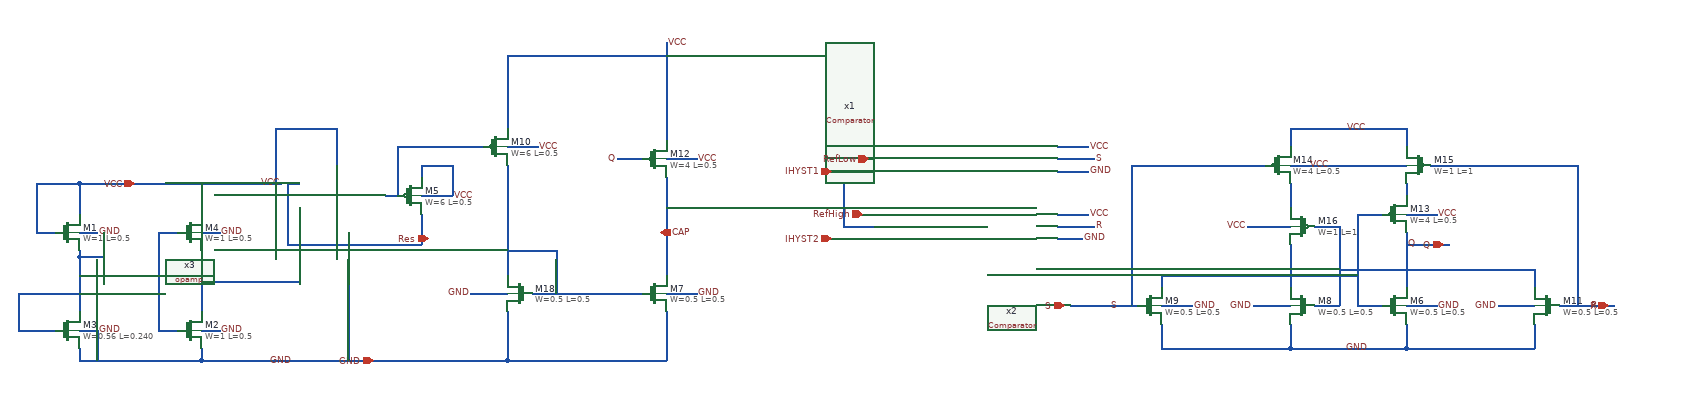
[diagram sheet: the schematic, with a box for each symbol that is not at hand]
v {xschem version=3.1.0 file_version=1.2 }
G {}
K {}
V {}
S {}
E {}
N 170 -340 200 -340 {lab=GND}
N 210 -500 210 -460 {lab=#net1}
N 170 -460 170 -370 {lab=#net1}
N 370 -310 370 -290 {lab=GND}
N 270 -290 370 -290 {lab=GND}
N 170 -310 170 -290 {lab=GND}
N 170 -290 270 -290 {lab=GND}
N 170 -470 170 -460 { lab=#net1}
N 1130 -370 1130 -290 { lab=GND}
N 870 -370 870 -290 { lab=GND}
N 810 -400 870 -400 { lab=GND}
N 1130 -400 1180 -400 { lab=GND}
N 370 -470 370 -370 { lab=#net2}
N 1130 -490 1130 -430 { lab=#net3}
N 910 -400 1090 -400 { lab=#net4}
N 870 -470 950 -470 { lab=#net4}
N 950 -470 950 -400 { lab=#net4}
N 170 -460 210 -460 { lab=#net1}
N 370 -580 370 -530 { lab=VCC}
N 170 -580 170 -530 { lab=VCC}
N 870 -480 870 -430 { lab=#net4}
N 170 -580 500 -580 { lab=VCC}
N 70 -340 130 -340 {
lab=#net1}
N 170 -500 200 -500 {lab=GND}
N 100 -500 130 -500 {
lab=VCC}
N 100 -580 100 -500 {
lab=VCC}
N 100 -580 170 -580 {
lab=VCC}
N 70 -400 70 -340 {
lab=#net1}
N 70 -400 170 -400 {
lab=#net1}
N 370 -340 400 -340 {lab=GND}
N 370 -500 400 -500 {lab=GND}
N 300 -500 330 -500 {
lab=#net1}
N 300 -500 300 -340 {
lab=#net1}
N 300 -340 330 -340 {
lab=#net1}
N 170 -430 300 -430 {
lab=#net1}
N 200 -340 200 -290 {
lab=GND}
N 370 -290 870 -290 {
lab=GND}
N 870 -290 1130 -290 {
lab=GND}
N 1050 -620 1090 -620 { lab=Q}
N 1130 -810 1130 -650 { lab=VCC}
N 870 -790 870 -670 { lab=VCC}
N 870 -640 920 -640 { lab=VCC}
N 1130 -620 1180 -620 { lab=VCC}
N 1130 -590 1130 -570 {
lab=#net3}
N 1130 -570 1130 -490 {
lab=#net3}
N 730 -560 780 -560 { lab=VCC}
N 870 -610 870 -480 {
lab=#net4}
N 870 -790 1130 -790 {
lab=VCC}
N 1420 -640 1470 -640 {
lab=#net3}
N 1420 -640 1420 -510 {
lab=#net3}
N 1420 -510 1470 -510 {
lab=#net3}
N 1450 -620 1470 -620 {
lab=RefLow}
N 1440 -530 1470 -530 {
lab=RefHigh}
N 1770 -640 1820 -640 { lab=VCC}
N 1770 -530 1820 -530 { lab=VCC}
N 1770 -490 1810 -490 {
lab=GND}
N 1770 -600 1820 -600 {
lab=GND}
N 730 -530 730 -490 {
lab=#net5}
N 2090 -380 2150 -380 { lab=GND}
N 2340 -380 2390 -380 { lab=GND}
N 2340 -470 2340 -410 { lab=Q}
N 2150 -460 2150 -410 { lab=#net6}
N 1940 -380 1990 -380 { lab=GND}
N 2490 -380 2550 -380 { lab=GND}
N 2150 -580 2150 -540 {
lab=#net7}
N 2340 -580 2340 -560 {
lab=#net8}
N 2340 -500 2340 -470 {
lab=Q}
N 2550 -440 2550 -410 {
lab=Q}
N 2340 -440 2550 -440 {
lab=Q}
N 1940 -430 1940 -410 {
lab=#net6}
N 1940 -430 2150 -430 {
lab=#net6}
N 1940 -350 1940 -310 {
lab=GND}
N 1940 -310 2150 -310 {
lab=GND}
N 2150 -350 2150 -310 {
lab=GND}
N 2150 -480 2150 -460 {
lab=#net6}
N 2150 -670 2150 -640 {
lab=VCC}
N 2340 -670 2340 -640 {
lab=VCC}
N 1870 -380 1900 -380 {
lab=S}
N 1890 -610 1890 -380 {
lab=S}
N 1890 -610 2110 -610 {
lab=S}
N 2590 -380 2640 -380 {
lab=R}
N 2620 -610 2620 -380 {
lab=R}
N 2380 -610 2620 -610 {
lab=R}
N 2190 -510 2230 -510 {
lab=Q}
N 2230 -510 2230 -380 {
lab=Q}
N 2190 -380 2230 -380 {
lab=Q}
N 2260 -530 2300 -530 {
lab=#net6}
N 2260 -530 2260 -380 {
lab=#net6}
N 2260 -380 2300 -380 {
lab=#net6}
N 2150 -670 2340 -670 {
lab=VCC}
N 2230 -440 2340 -440 {
lab=Q}
N 2150 -430 2260 -430 {
lab=#net6}
N 1770 -620 1830 -620 {
lab=S}
N 1770 -510 1830 -510 {
lab=R}
N 2150 -310 2340 -310 {
lab=GND}
N 2340 -350 2340 -310 {
lab=GND}
N 2550 -350 2550 -310 {
lab=GND}
N 2340 -310 2550 -310 {
lab=GND}
N 2150 -610 2180 -610 {
lab=VCC}
N 2180 -610 2340 -610 {
lab=VCC}
N 2340 -530 2390 -530 {
lab=VCC}
N 2080 -510 2150 -510 {
lab=VCC}
N 590 -670 590 -610 {
lab=VCC}
N 490 -670 590 -670 {
lab=VCC}
N 490 -670 490 -580 {
lab=VCC}
N 610 -500 610 -290 {
lab=GND}
N 670 -560 690 -560 {
lab=#net9}
N 690 -640 830 -640 {
lab=#net9}
N 690 -640 690 -560 {
lab=#net9}
N 530 -540 530 -420 {
lab=#net2}
N 370 -420 530 -420 {
lab=#net2}
N 510 -580 530 -580 {
lab=#net5}
N 510 -580 510 -480 {
lab=#net5}
N 510 -480 730 -480 {
lab=#net5}
N 730 -490 730 -480 {
lab=#net5}
N 730 -610 730 -590 {
lab=VCC}
N 730 -610 780 -610 {
lab=VCC}
N 780 -610 780 -560 {
lab=VCC}
N 1130 -540 1420 -540 {
lab=#net3}
N 1390 -490 1470 -490 {
lab=IHYST2}
N 1390 -600 1470 -600 {
lab=IHYST1}
N 2340 -480 2410 -480 {
lab=GND}
N 2640 -380 2680 -380 {
lab=R}
N 1790 -380 1870 -380 {
lab=S}
C {devices/lab_pin.sym} 200 -340 0 1 {name=p187 lab=GND}
C {devices/lab_pin.sym} 500 -580 1 0 {name=p192 lab=VCC}
C {devices/lab_pin.sym} 810 -400 0 0 {name=p3 lab=GND}
C {devices/lab_pin.sym} 1180 -400 0 1 {name=p5 lab=GND}
C {devices/lab_pin.sym} 520 -290 3 0 {name=p9 lab=GND}
C {sky130_fd_pr/nfet_g5v0d10v5.sym} 1110 -400 0 0 {name=M7
L=0.5
W=0.5
nf=1
mult=1
ad="'int((nf+1)/2) * W/nf * 0.29'" 
pd="'2*int((nf+1)/2) * (W/nf + 0.29)'"
as="'int((nf+2)/2) * W/nf * 0.29'" 
ps="'2*int((nf+2)/2) * (W/nf + 0.29)'"
nrd="'0.29 / W'" nrs="'0.29 / W'"
sa=0 sb=0 sd=0
model=nfet_g5v0d10v5
spiceprefix=X
}
C {sky130_fd_pr/nfet_g5v0d10v5.sym} 890 -400 0 1 {name=M18
L=0.5
W=0.5
nf=1
mult=1
ad="'int((nf+1)/2) * W/nf * 0.29'" 
pd="'2*int((nf+1)/2) * (W/nf + 0.29)'"
as="'int((nf+2)/2) * W/nf * 0.29'" 
ps="'2*int((nf+2)/2) * (W/nf + 0.29)'"
nrd="'0.29 / W'" nrs="'0.29 / W'"
sa=0 sb=0 sd=0
model=nfet_g5v0d10v5
spiceprefix=X
}
C {sky130_fd_pr/nfet_g5v0d10v5.sym} 150 -340 0 0 {name=M3
L=0.240
W=0.56
nf=1
mult=1
ad="'int((nf+1)/2) * W/nf * 0.29'" 
pd="'2*int((nf+1)/2) * (W/nf + 0.29)'"
as="'int((nf+2)/2) * W/nf * 0.29'" 
ps="'2*int((nf+2)/2) * (W/nf + 0.29)'"
nrd="'0.29 / W'" nrs="'0.29 / W'"
sa=0 sb=0 sd=0
model=nfet_g5v0d10v5
spiceprefix=X
}
C {devices/iopin.sym} 260 -580 0 0 {name=p17 lab=VCC}
C {devices/iopin.sym} 650 -290 0 0 {name=p20 lab=GND}
C {devices/ipin.sym} 740 -490 0 0 {name=p21 lab=Res}
C {sky130_fd_pr/nfet_g5v0d10v5.sym} 150 -500 0 0 {name=M1
L=0.5
W=1
nf=1
mult=1
ad="'int((nf+1)/2) * W/nf * 0.29'" 
pd="'2*int((nf+1)/2) * (W/nf + 0.29)'"
as="'int((nf+2)/2) * W/nf * 0.29'" 
ps="'2*int((nf+2)/2) * (W/nf + 0.29)'"
nrd="'0.29 / W'" nrs="'0.29 / W'"
sa=0 sb=0 sd=0
model=nfet_g5v0d10v5
spiceprefix=X
}
C {devices/lab_pin.sym} 200 -500 0 1 {name=p1 lab=GND}
C {devices/lab_pin.sym} 400 -340 0 1 {name=p2 lab=GND}
C {sky130_fd_pr/nfet_g5v0d10v5.sym} 350 -340 0 0 {name=M2
L=0.5
W=1
nf=1
mult=1
ad="'int((nf+1)/2) * W/nf * 0.29'" 
pd="'2*int((nf+1)/2) * (W/nf + 0.29)'"
as="'int((nf+2)/2) * W/nf * 0.29'" 
ps="'2*int((nf+2)/2) * (W/nf + 0.29)'"
nrd="'0.29 / W'" nrs="'0.29 / W'"
sa=0 sb=0 sd=0
model=nfet_g5v0d10v5
spiceprefix=X
}
C {devices/lab_pin.sym} 400 -500 0 1 {name=p4 lab=GND}
C {sky130_fd_pr/nfet_g5v0d10v5.sym} 350 -500 0 0 {name=M4
L=0.5
W=1
nf=1
mult=1
ad="'int((nf+1)/2) * W/nf * 0.29'" 
pd="'2*int((nf+1)/2) * (W/nf + 0.29)'"
as="'int((nf+2)/2) * W/nf * 0.29'" 
ps="'2*int((nf+2)/2) * (W/nf + 0.29)'"
nrd="'0.29 / W'" nrs="'0.29 / W'"
sa=0 sb=0 sd=0
model=nfet_g5v0d10v5
spiceprefix=X
}
C {devices/lab_pin.sym} 1180 -620 0 1 {name=p6 lab=VCC}
C {devices/lab_pin.sym} 920 -640 0 1 {name=p7 lab=VCC}
C {sky130_fd_pr/pfet_g5v0d10v5.sym} 1110 -620 0 0 {name=M12
L=0.5
W=4
nf=1
mult=1
ad="'int((nf+1)/2) * W/nf * 0.29'" 
pd="'2*int((nf+1)/2) * (W/nf + 0.29)'"
as="'int((nf+2)/2) * W/nf * 0.29'" 
ps="'2*int((nf+2)/2) * (W/nf + 0.29)'"
nrd="'0.29 / W'" nrs="'0.29 / W'"
sa=0 sb=0 sd=0
model=pfet_g5v0d10v5
spiceprefix=X
}
C {sky130_fd_pr/pfet_g5v0d10v5.sym} 850 -640 0 0 {name=M10
L=0.5
W=6
nf=1
mult=1
ad="'int((nf+1)/2) * W/nf * 0.29'" 
pd="'2*int((nf+1)/2) * (W/nf + 0.29)'"
as="'int((nf+2)/2) * W/nf * 0.29'" 
ps="'2*int((nf+2)/2) * (W/nf + 0.29)'"
nrd="'0.29 / W'" nrs="'0.29 / W'"
sa=0 sb=0 sd=0
model=pfet_g5v0d10v5
spiceprefix=X
}
C {devices/lab_pin.sym} 780 -560 0 1 {name=p8 lab=VCC}
C {sky130_fd_pr/pfet_g5v0d10v5.sym} 710 -560 0 0 {name=M5
L=0.5
W=6
nf=1
mult=1
ad="'int((nf+1)/2) * W/nf * 0.29'" 
pd="'2*int((nf+1)/2) * (W/nf + 0.29)'"
as="'int((nf+2)/2) * W/nf * 0.29'" 
ps="'2*int((nf+2)/2) * (W/nf + 0.29)'"
nrd="'0.29 / W'" nrs="'0.29 / W'"
sa=0 sb=0 sd=0
model=pfet_g5v0d10v5
spiceprefix=X
}
C {Comparator.sym} 1620 -620 0 0 {name=x1}
C {Comparator.sym} 1620 -510 0 0 {name=x2}
C {devices/ipin.sym} 1460 -620 0 0 {name=p10 lab=RefLow}
C {devices/ipin.sym} 1450 -530 0 0 {name=p11 lab=RefHigh}
C {devices/lab_pin.sym} 1820 -640 0 1 {name=p12 lab=VCC}
C {devices/lab_pin.sym} 1820 -530 0 1 {name=p13 lab=VCC}
C {devices/lab_pin.sym} 1820 -600 0 1 {name=p14 lab=GND}
C {devices/lab_pin.sym} 1810 -490 0 1 {name=p15 lab=GND}
C {devices/opin.sym} 1120 -500 0 0 {name=p16 lab=CAP}
C {devices/lab_pin.sym} 2090 -380 0 0 {name=p18 lab=GND}
C {devices/lab_pin.sym} 2390 -380 0 1 {name=p19 lab=GND}
C {sky130_fd_pr/nfet_g5v0d10v5.sym} 2320 -380 0 0 {name=M6
L=0.5
W=0.5
nf=1
mult=1
ad="'int((nf+1)/2) * W/nf * 0.29'" 
pd="'2*int((nf+1)/2) * (W/nf + 0.29)'"
as="'int((nf+2)/2) * W/nf * 0.29'" 
ps="'2*int((nf+2)/2) * (W/nf + 0.29)'"
nrd="'0.29 / W'" nrs="'0.29 / W'"
sa=0 sb=0 sd=0
model=nfet_g5v0d10v5
spiceprefix=X
}
C {sky130_fd_pr/nfet_g5v0d10v5.sym} 2170 -380 0 1 {name=M8
L=0.5
W=0.5
nf=1
mult=1
ad="'int((nf+1)/2) * W/nf * 0.29'" 
pd="'2*int((nf+1)/2) * (W/nf + 0.29)'"
as="'int((nf+2)/2) * W/nf * 0.29'" 
ps="'2*int((nf+2)/2) * (W/nf + 0.29)'"
nrd="'0.29 / W'" nrs="'0.29 / W'"
sa=0 sb=0 sd=0
model=nfet_g5v0d10v5
spiceprefix=X
}
C {devices/lab_pin.sym} 1990 -380 0 1 {name=p22 lab=GND}
C {sky130_fd_pr/nfet_g5v0d10v5.sym} 1920 -380 0 0 {name=M9
L=0.5
W=0.5
nf=1
mult=1
ad="'int((nf+1)/2) * W/nf * 0.29'" 
pd="'2*int((nf+1)/2) * (W/nf + 0.29)'"
as="'int((nf+2)/2) * W/nf * 0.29'" 
ps="'2*int((nf+2)/2) * (W/nf + 0.29)'"
nrd="'0.29 / W'" nrs="'0.29 / W'"
sa=0 sb=0 sd=0
model=nfet_g5v0d10v5
spiceprefix=X
}
C {devices/lab_pin.sym} 2490 -380 0 0 {name=p23 lab=GND}
C {sky130_fd_pr/nfet_g5v0d10v5.sym} 2570 -380 0 1 {name=M11
L=0.5
W=0.5
nf=1
mult=1
ad="'int((nf+1)/2) * W/nf * 0.29'" 
pd="'2*int((nf+1)/2) * (W/nf + 0.29)'"
as="'int((nf+2)/2) * W/nf * 0.29'" 
ps="'2*int((nf+2)/2) * (W/nf + 0.29)'"
nrd="'0.29 / W'" nrs="'0.29 / W'"
sa=0 sb=0 sd=0
model=nfet_g5v0d10v5
spiceprefix=X
}
C {sky130_fd_pr/pfet_g5v0d10v5.sym} 2320 -530 0 0 {name=M13
L=0.5
W=4
nf=1
mult=1
ad="'int((nf+1)/2) * W/nf * 0.29'" 
pd="'2*int((nf+1)/2) * (W/nf + 0.29)'"
as="'int((nf+2)/2) * W/nf * 0.29'" 
ps="'2*int((nf+2)/2) * (W/nf + 0.29)'"
nrd="'0.29 / W'" nrs="'0.29 / W'"
sa=0 sb=0 sd=0
model=pfet_g5v0d10v5
spiceprefix=X
}
C {sky130_fd_pr/pfet_g5v0d10v5.sym} 2130 -610 0 0 {name=M14
L=0.5
W=4
nf=1
mult=1
ad="'int((nf+1)/2) * W/nf * 0.29'" 
pd="'2*int((nf+1)/2) * (W/nf + 0.29)'"
as="'int((nf+2)/2) * W/nf * 0.29'" 
ps="'2*int((nf+2)/2) * (W/nf + 0.29)'"
nrd="'0.29 / W'" nrs="'0.29 / W'"
sa=0 sb=0 sd=0
model=pfet_g5v0d10v5
spiceprefix=X
}
C {sky130_fd_pr/pfet_g5v0d10v5.sym} 2360 -610 0 1 {name=M15
L=1
W=1
nf=1
mult=1
ad="'int((nf+1)/2) * W/nf * 0.29'" 
pd="'2*int((nf+1)/2) * (W/nf + 0.29)'"
as="'int((nf+2)/2) * W/nf * 0.29'" 
ps="'2*int((nf+2)/2) * (W/nf + 0.29)'"
nrd="'0.29 / W'" nrs="'0.29 / W'"
sa=0 sb=0 sd=0
model=pfet_g5v0d10v5
spiceprefix=X
}
C {sky130_fd_pr/pfet_g5v0d10v5.sym} 2170 -510 0 1 {name=M16
L=1
W=1
nf=1
mult=1
ad="'int((nf+1)/2) * W/nf * 0.29'" 
pd="'2*int((nf+1)/2) * (W/nf + 0.29)'"
as="'int((nf+2)/2) * W/nf * 0.29'" 
ps="'2*int((nf+2)/2) * (W/nf + 0.29)'"
nrd="'0.29 / W'" nrs="'0.29 / W'"
sa=0 sb=0 sd=0
model=pfet_g5v0d10v5
spiceprefix=X
}
C {devices/lab_pin.sym} 1830 -620 0 1 {name=p24 lab=S}
C {devices/lab_pin.sym} 1830 -510 0 1 {name=p25 lab=R}
C {devices/lab_pin.sym} 1870 -380 0 0 {name=p26 lab=S}
C {devices/lab_pin.sym} 2640 -380 0 1 {name=p27 lab=R}
C {devices/lab_pin.sym} 2340 -480 0 1 {name=p28 lab=Q}
C {devices/lab_pin.sym} 1050 -620 0 0 {name=p29 lab=Q}
C {devices/lab_pin.sym} 2240 -670 0 1 {name=p30 lab=VCC}
C {devices/lab_pin.sym} 2280 -310 0 0 {name=p31 lab=GND}
C {devices/lab_pin.sym} 2180 -610 0 1 {name=p32 lab=VCC}
C {devices/lab_pin.sym} 2390 -530 0 1 {name=p33 lab=VCC}
C {devices/lab_pin.sym} 1130 -810 0 1 {name=p34 lab=VCC}
C {devices/lab_pin.sym} 2080 -510 0 0 {name=p35 lab=VCC}
C {caravel_fulgor_opamp/xschem/opamp_julia/sch/opamp.sym} 600 -560 0 0 {name=x3}
C {devices/ipin.sym} 1400 -600 0 0 {name=p36 lab=IHYST1}
C {devices/ipin.sym} 1400 -490 0 0 {name=p37 lab=IHYST2}
C {devices/iopin.sym} 1780 -380 0 0 {name=p38 lab=S}
C {devices/iopin.sym} 2670 -380 0 0 {name=p39 lab=R}
C {devices/iopin.sym} 2400 -480 0 0 {name=p40 lab=Q}
